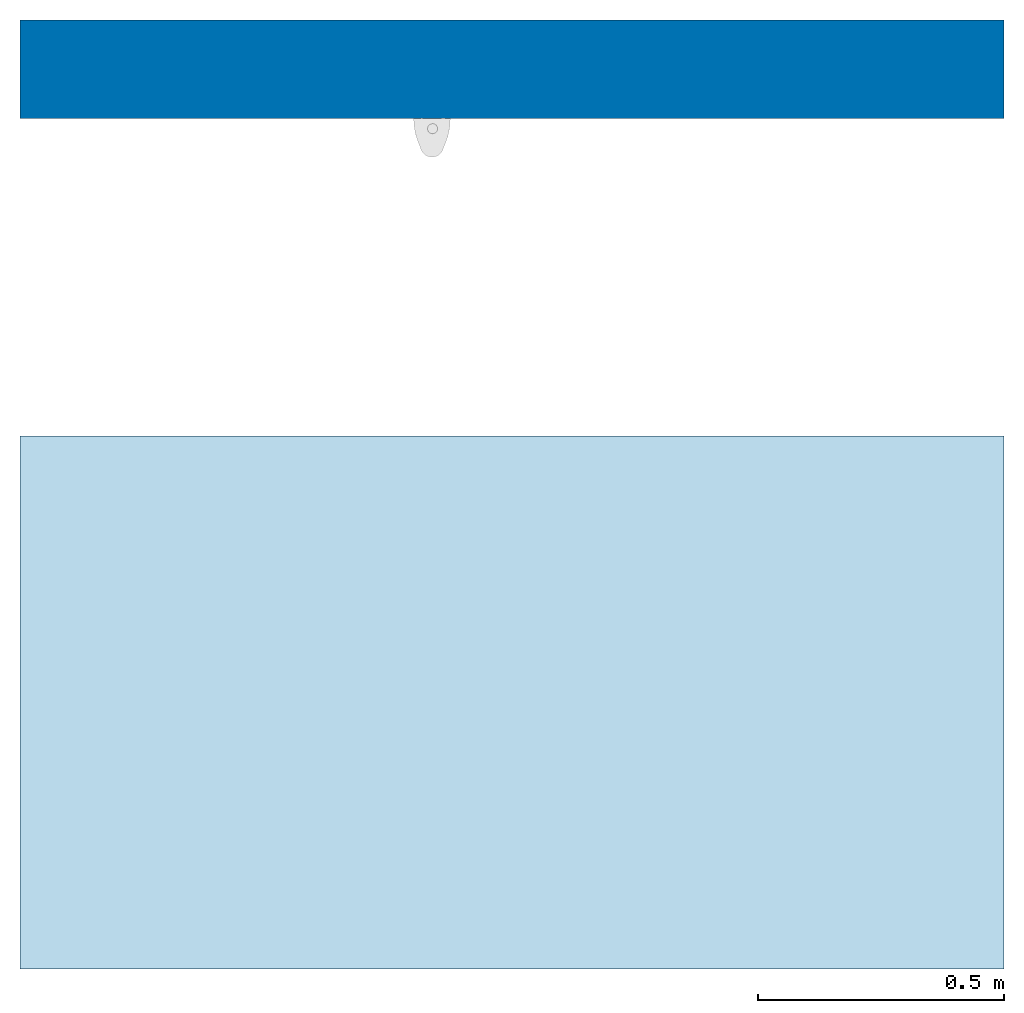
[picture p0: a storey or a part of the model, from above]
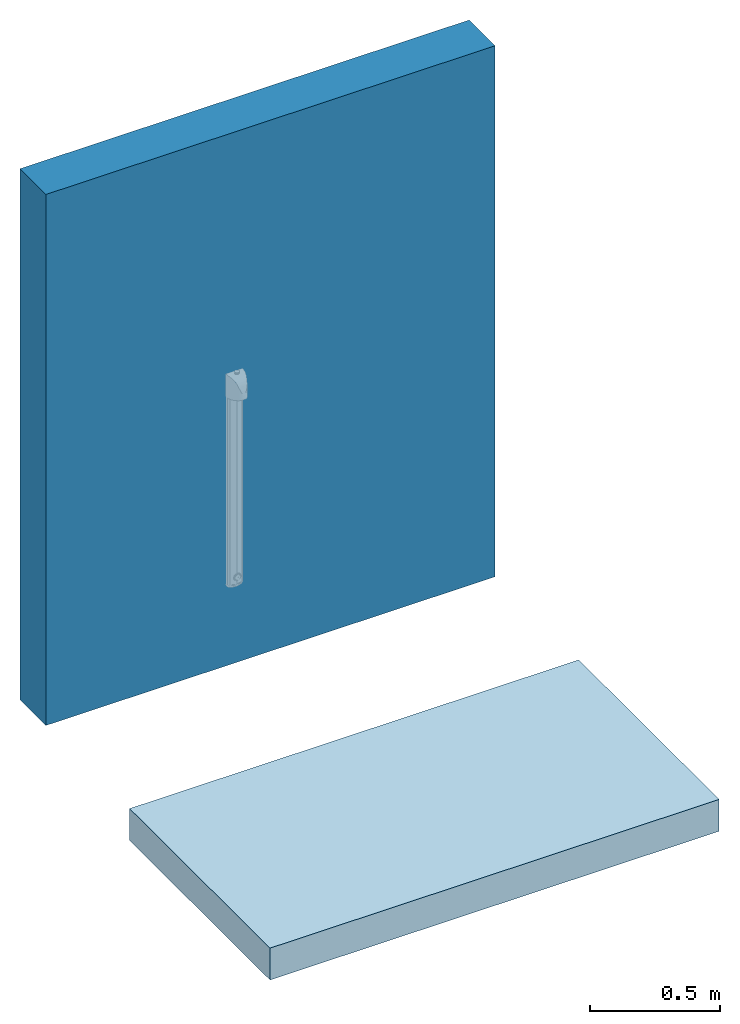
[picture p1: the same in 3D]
Properties of the parts of a building model (IFC2X3)

# File
Description: ViewDefinition [CoordinationView]
File name: Project Number
Time: 2016-07-05T09:23:01
Written by: Autodesk Revit Architecture 2011 - 1.0
Made in: 20100326_1700(x64)

# IfcProject, Project Number
Phase: Project Status

# IfcSite, Default
RefLatitude: 42, 21, 30, 344238; RefLongitude: -71, -3, -35, -194702; RefElevation: 0 mm

# IfcBuilding
Pset_BuildingCommon - NumberOfStoreys: 1
PSet_Revit_Other - Project Issue Date: Issue Date; Project Status: Project Status; Client Name: Owner; Project Address: Enter address here; Project Name: Project Name; Project Number: Project Number

# IfcBuildingStorey, Level 1
Elevation: 0 mm
PSet_Revit_Identity Data - Name: Level 1
PSet_Revit_Constraints - Elevation: 0 mm
PSet_Revit_Type_Graphics - Line Weight: 1; Color: 0; Line Pattern: Centre; Symbol: M_Level Head - Circle; Symbol at End 1 Default: no; Symbol at End 2 Default: yes
PSet_Revit_Type_Constraints - Elevation Base: 0
PSet_Revit_Type_Dimensions - Automatic Room Computation Height: no; Computation Height: 1200 mm

# IfcBuildingElementProxy: Type 1, 714700-FR-2:Type 1:Type 1:163946
In: Level 1
PSet_Revit_Constraints - Level: Level 1; Elevation: 367.457 mm
PSet_Revit_Mechanical - System Type: Domestic Hot Water; System Name: Default Domestic Hot Water (Polantis_Production)
PSet_Revit_Identity Data - Mark: 21
PSet_Revit_Phasing - Phase Created: New Construction
PSet_Revit_Type_Identity Data - URL: http://www.delabie.fr/; Type Comments: Panneau de douche temporisé; Technologie: Temporisée; Référence: 714700; Raccordement: M1/2"; Profondeur: 20 mm; Model: SPORTING 2; Manufacturer: DELABIE; Lien notice d'installation: http://www.delabie.fr/produits/714700; Lien fiche produit: http://www.delabie.fr/produits/714700; Lien certification: http://www.delabie.fr/produits/714700; Lien CCTP: http://www.delabie.fr/produits/714700; Largeur: 70 mm; Hauteur: 1030 mm; Finition: Aluminium anodisé et chrome satiné; Famille de produits: Douche; Débit (l/s): 0,1 l/s à 3 bar; Débit (l/min): 6 l/min à 3 bar; Description: DELABIE, fabricant français, est le leader européen de l'équipement sanitaire pour les établissements recevant du public. Robinetteries, solutions pour personnes à mobilité réduite, appareils sanitaires, destinés aux écoles, lieux de loisirs, bureaux, hôpitaux, aéroports, ...; Descriptif: Panneau de douche temporisé: Panneau aluminium anodisé et chrome satiné. Raccord orientable pour alimentation par le haut ou par l'arrière. Structure extra plate avec fixations invisibles. Déclenchement souple. Purge automatique mécanique à chaque utilisation. Temporisation ~30 sec. Débit 6 l/min à 3 bar. Pomme de douche fixe inviolable à diffuseur antitartre avec régulateur automatique de débit. Jet orientable verrouillable. Clapet antiretour et filtre accessibles. Robinet d’arrêt intégré. Raccordement M1/2" pour alimentation en eau mitigée.; OmniClass Number: 23.45.00.00; OmniClass Title: Sanitary, Laundry, and Cleaning Equipment
PSet_Revit_Type_Dimensions - Radius: 10.3 mm
PSet_Revit_Type_Plumbing - HW Connection: no; CW Connection: no

# IfcSlab: Floor:Generic 150mm, Floor:Generic 150mm:135115
In: Level 1
PredefinedType: FLOOR; Material: Default Floor 150 mm
Pset_SlabCommon - Reference: Floor:Generic 150mm; IsExternal: no; LoadBearing: yes
PSet_Revit_Constraints - Level: Level 1; Height Offset From Level: 0 mm; Room Bounding: yes; Related to Mass: no
PSet_Revit_Structural - Structural: no
PSet_Revit_Phasing - Phase Created: New Construction
PSet_Revit_Dimensions - Perimeter: 6166.51 mm; Area: 2166512 mm2; Volume: 324976850 mm3; Thickness: 150 mm
PSet_Revit_Analytical Model - Vertical Projection: Default
PSet_Revit_Structural Analysis - Structural Usage: 3
PSet_Revit_Type_Construction - Default Thickness: 150 mm; Function: 0
PSet_Revit_Type_Graphics - Coarse Scale Fill Color: 0

# IfcWallStandardCase: Basic Wall:Generic - 200mm:398, Basic Wall:Generic - 200mm:127598
In: Level 1
Material: Default Wall 200 mm
Pset_WallCommon - Reference: Basic Wall:Generic - 200mm; LoadBearing: no; ExtendToStructure: no; IsExternal: yes
PSet_Revit_Constraints - Location Line: 0; Base Constraint: Level 1; Base Offset: 0 mm; Base is Attached: no; Base Extension Distance: 0 mm; Unconnected Height: 2500 mm; Top Offset: 0 mm; Top is Attached: no; Top Extension Distance: 0 mm; Room Bounding: yes; Related to Mass: no
PSet_Revit_Phasing - Phase Created: New Construction
PSet_Revit_Structural - Structural Usage: 0
PSet_Revit_Dimensions - Length: 2000 mm; Area: 5000000 mm2; Volume: 1000000000 mm3
PSet_Revit_Type_Construction - Wrapping at Inserts: 0; Wrapping at Ends: 0; Width: 200 mm; Function: 1
PSet_Revit_Type_Graphics - Coarse Scale Fill Color: 0
